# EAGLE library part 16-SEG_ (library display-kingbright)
16 SEGMENT SINGLE DIGIT ALPHANUMERIC NUMERIC DISPLAY

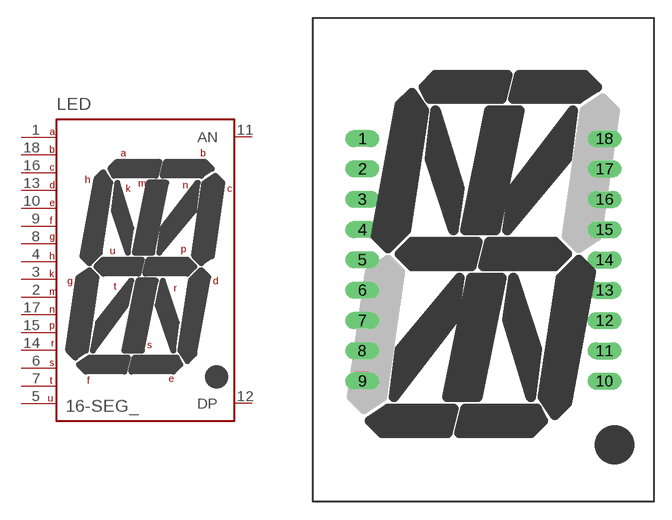
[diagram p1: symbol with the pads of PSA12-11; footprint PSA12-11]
Designator prefix LED

## 16-SEG_PSA12-11 (OC_FARNELL: unknown; OC_NEWARK: unknown)  [PSA12-11]
1  A  pas
2  M  pas
3  K  pas
4  H  pas
5  U  pas
6  S  pas
7  T  pas
8  G  pas
9  F  pas
10  E  pas
11  AN  pas
12  DP  pas
13  D  pas
14  R  pas
15  P  pas
16  C  pas
17  N  pas
18  B  pas

## Footprint PSA12-11 (pad centres in mm)
30.48mm(1.2 INCH) 16 SEGMENT SINGLE DIGIT ALPHANUMERIC NUMERIC DISPLAY Source: PSA12-11EWA(Ver1189413040.8).pdf
drill 0.7 pad 1.422 long: 1 -10.16,10.16; 2 -10.16,7.62; 3 -10.16,5.08; 4 -10.16,2.54; 5 -10.16,0; 6 -10.16,-2.54; 7 -10.16,-5.08; 8 -10.16,-7.62; 9 -10.16,-10.16; 10 10.16,-10.16; 11 10.16,-7.62; 12 10.16,-5.08; 13 10.16,-2.54; 14 10.16,0; 15 10.16,2.54; 16 10.16,5.08; 17 10.16,7.62; 18 10.16,10.16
